One B-rep face of a CAD part: STEP entity #168.
In plain terms, the planar face has unit normal (1, 0, 0).
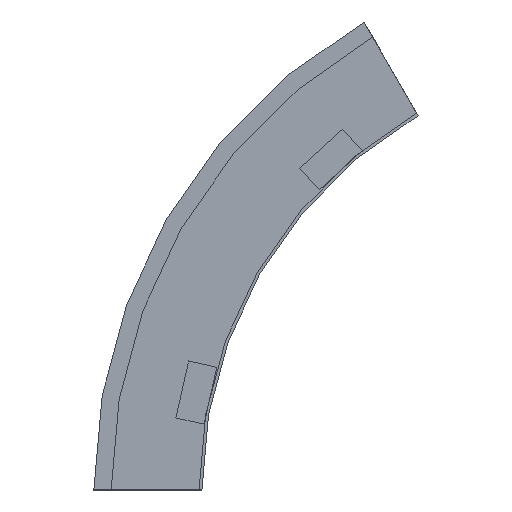
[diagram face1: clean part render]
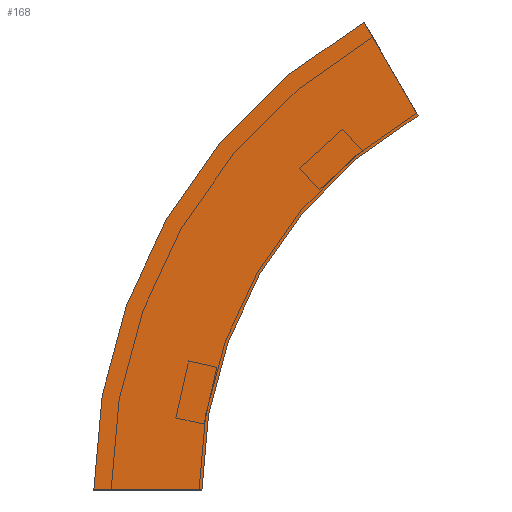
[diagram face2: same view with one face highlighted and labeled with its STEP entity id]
Its self-contained STEP definition (entity closure, numbers rounded to 3 decimals):
#17 = DIRECTION ( 'NONE',  ( 1., 0., 0. ) ) ;
#21 = VERTEX_POINT ( 'NONE', #104 ) ;
#31 = EDGE_CURVE ( 'NONE', #411, #519, #50, .T. ) ;
#44 = ORIENTED_EDGE ( 'NONE', *, *, #481, .F. ) ;
#50 = LINE ( 'NONE', #106, #82 ) ;
#56 = AXIS2_PLACEMENT_3D ( 'NONE', #260, #497, #427 ) ;
#70 = AXIS2_PLACEMENT_3D ( 'NONE', #71, #384, #79 ) ;
#71 = CARTESIAN_POINT ( 'NONE',  ( 0., -300., 0. ) ) ;
#75 = DIRECTION ( 'NONE',  ( 0., 0.5, 0.866 ) ) ;
#76 = VERTEX_POINT ( 'NONE', #88 ) ;
#79 = DIRECTION ( 'NONE',  ( 0., 1., 0. ) ) ;
#82 = VECTOR ( 'NONE', #277, 1000. ) ;
#88 = CARTESIAN_POINT ( 'NONE',  ( 0., -112.5, 324.76 ) ) ;
#104 = CARTESIAN_POINT ( 'NONE',  ( 0., -150., 259.808 ) ) ;
#106 = CARTESIAN_POINT ( 'NONE',  ( 0., 0., 0. ) ) ;
#120 = CARTESIAN_POINT ( 'NONE',  ( 0., -150., 259.808 ) ) ;
#164 = PLANE ( 'NONE',  #462 ) ;
#168 = ADVANCED_FACE ( 'NONE', ( #247 ), #164, .T. ) ;
#171 = EDGE_CURVE ( 'NONE', #519, #76, #476, .T. ) ;
#188 = ORIENTED_EDGE ( 'NONE', *, *, #31, .T. ) ;
#198 = VECTOR ( 'NONE', #75, 1000. ) ;
#206 = DIRECTION ( 'NONE',  ( 0., 0., -1. ) ) ;
#208 = LINE ( 'NONE', #120, #198 ) ;
#247 = FACE_OUTER_BOUND ( 'NONE', #477, .T. ) ;
#260 = CARTESIAN_POINT ( 'NONE',  ( 0., -300., 0. ) ) ;
#277 = DIRECTION ( 'NONE',  ( 0., 1., 0. ) ) ;
#289 = EDGE_CURVE ( 'NONE', #21, #76, #208, .T. ) ;
#311 = ORIENTED_EDGE ( 'NONE', *, *, #289, .F. ) ;
#384 = DIRECTION ( 'NONE',  ( 1., 0., 0. ) ) ;
#411 = VERTEX_POINT ( 'NONE', #488 ) ;
#426 = CARTESIAN_POINT ( 'NONE',  ( 0., 75., 0. ) ) ;
#427 = DIRECTION ( 'NONE',  ( 0., 1., 0. ) ) ;
#462 = AXIS2_PLACEMENT_3D ( 'NONE', #553, #17, #206 ) ;
#472 = ORIENTED_EDGE ( 'NONE', *, *, #171, .T. ) ;
#476 = CIRCLE ( 'NONE', #56, 375. ) ;
#477 = EDGE_LOOP ( 'NONE', ( #472, #311, #44, #188 ) ) ;
#481 = EDGE_CURVE ( 'NONE', #411, #21, #513, .T. ) ;
#488 = CARTESIAN_POINT ( 'NONE',  ( 0., 0., 0. ) ) ;
#497 = DIRECTION ( 'NONE',  ( 1., 0., 0. ) ) ;
#513 = CIRCLE ( 'NONE', #70, 300. ) ;
#519 = VERTEX_POINT ( 'NONE', #426 ) ;
#553 = CARTESIAN_POINT ( 'NONE',  ( 0., 0., 0. ) ) ;
